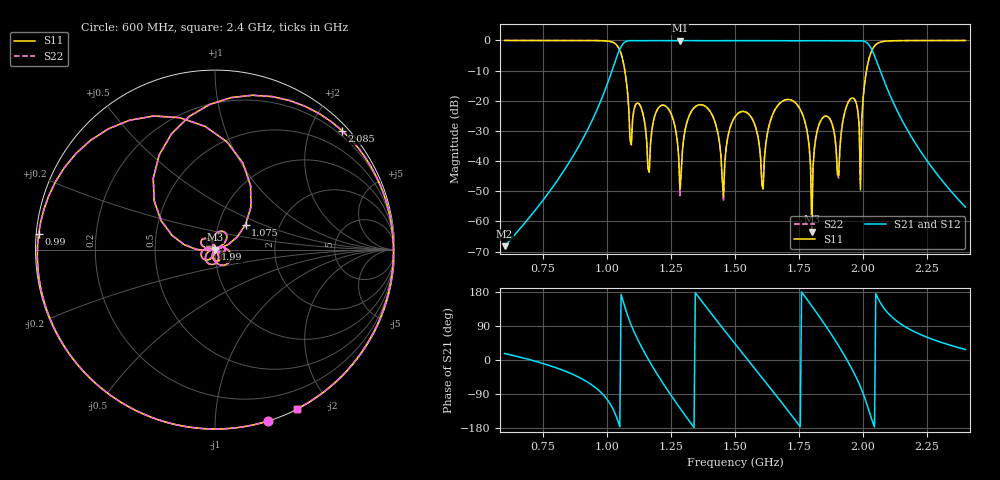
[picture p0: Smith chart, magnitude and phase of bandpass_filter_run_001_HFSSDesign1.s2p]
! Touchstone file exported from HFSS 2025.2.4
!  File:  F:/00_Inbox_%x4E34%x65F6%x6536%x4EF6%x7BB1/ansys%x4E34%x65F6%x5B58%x653E/project/bandpass_filter_run_001.aedt
!  Generated:  04:04:03 PM Aug 17, 2026
!  Design:  HFSSDesign1
!  Project:  bandpass_filter_run_001
!  Setup:  1p5GHz
!  Solution:  0p6_2p4GHz
! Variables:
!  Cavity_x = 50.8mm
!  Cavity_y = 86.36mm
!  Cavity_z = 15.875mm
!  L1 = 50um
!  L2 = -90um
!  L3 = 40um
!  L4 = -45um
!  dg0 = -80um
!  dg1 = -10um
!  dg2 = 25um
!  dg_feed = -70um
!  line_thickness = 60mil
# GHz S MA R 50.000000
! Terminal data exported
! Port[1] = T1
! Port[2] = T2
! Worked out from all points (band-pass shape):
!   361 points, 600 MHz to 2.4 GHz, reference 50 ohm
!   highest |S21| = -0.05 dB at 1.285 GHz (marker M1); lowest = -68.2 dB at 600 MHz (marker M2)
!   |S21| within 3 dB of the highest: 1.049 GHz to 2.034 GHz (985 MHz wide, 63.9 % of centre)
!   lowest |S11| = -63.4 dB at 1.8 GHz (marker M3), VSWR 1.00, Z = 50.1 - j0.0429 ohm
!   |S11| at or under -10 dB: 1.07 GHz to 2.014 GHz (944.1 MHz wide, 61.2 % of centre)
!   |S22| runs from -53.2 to 0.0 dB; largest |S21 - S12| = 8.4e-14
!   S11 on the Smith chart (normalised r, x): 600 MHz: 0.00, -1.36; 990 MHz: 0.01, +0.04; 1.075 GHz: 1.34, +0.39; 1.99 GHz: 1.00, +0.01; 2.085 GHz: 0.11, +2.53; 2.4 GHz: 0.00, -1.65
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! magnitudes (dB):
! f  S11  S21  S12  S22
! 600 MHz  0.0  -68.2  -68.2  0.0
! 900 MHz  0.0  -33.5  -33.5  0.0
! 990 MHz  -0.1  -17.0  -17.0  -0.1
! 1.075 GHz  -13.2  -0.3  -0.3  -13.2
! 1.165 GHz  -43.7  -0.1  -0.1  -43.5
! 1.2 GHz  -22.5  -0.1  -0.1  -22.5
! 1.285 GHz  -49.5  -0.1  -0.1  -51.4
! 1.335 GHz  -22.8  -0.1  -0.1  -22.8
! 1.455 GHz  -51.7  -0.1  -0.1  -53.2
! 1.5 GHz  -25.3  -0.1  -0.1  -25.3
! 1.61 GHz  -49.2  -0.1  -0.1  -47.1
! 1.75 GHz  -22.1  -0.1  -0.1  -22.1
! 1.79 GHz  -35.4  -0.1  -0.1  -35.4
! 1.8 GHz  -63.4  -0.1  -0.1  -52.4
! 1.845 GHz  -25.4  -0.1  -0.1  -25.4
! 1.905 GHz  -44.9  -0.1  -0.1  -45.6
! 1.97 GHz  -19.9  -0.2  -0.2  -19.9
! 1.99 GHz  -49.5  -0.1  -0.1  -46.3
! 2.015 GHz  -9.4  -0.7  -0.7  -9.4
! 2.085 GHz  -0.3  -14.0  -14.0  -0.3
! 2.1 GHz  -0.2  -17.1  -17.1  -0.2
! 2.4 GHz  0.0  -55.2  -55.2  0.0
